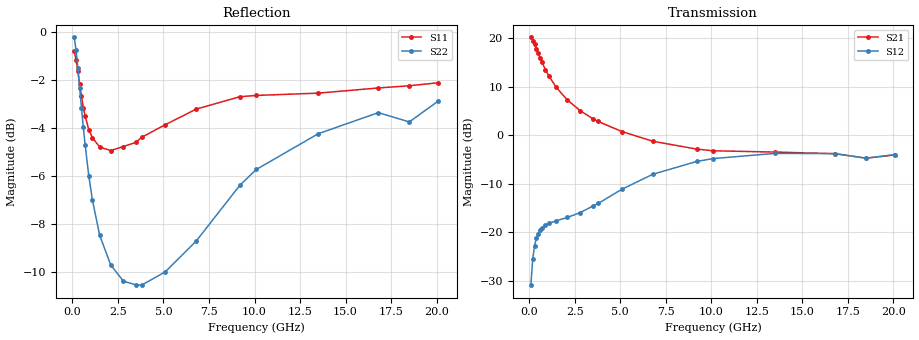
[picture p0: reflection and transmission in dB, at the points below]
!  Infineon Technologies AG
! BFR380L3 , PF131585-7, No.6, Th 09.10.01, soldered on pcb-board, measured with PP GSG850
!  Vce=4.0 V,  Ic=3.0 mA
! Common Emitter S-Parameters:  15. November 2001
#  GHz  S  MA  R  50
! f  S11  S21  S12  S22
! GHz  Mag  Ang  Mag  Ang  Mag  Ang  Mag  Ang
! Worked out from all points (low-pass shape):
!   201 points, 100 MHz to 20.1 GHz, reference 50 ohm
!   highest |S21| = 20.22 dB at 100 MHz (marker M1); lowest = -4.7 dB at 18.5 GHz (marker M2)
!   |S21| within 3 dB of the highest: start of sweep to 471.9 MHz
!   lowest |S11| = -4.9 dB at 2.1 GHz (marker M3), VSWR 3.62, Z = 13.8 - j1.7 ohm
!   |S11| at or under -10 dB: nowhere
!   |S22| runs from -10.5 to -0.2 dB; largest |S21 - S12| = 10
!   S11 on the Smith chart (normalised r, x): 100 MHz: 1.31, -5.09; 400 MHz: 0.35, -1.31; 1.1 GHz: 0.29, -0.38; 3.8 GHz: 0.27, +0.27; 9.2 GHz: 0.33, +1.06; 20.1 GHz: 1.00, +2.52
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0.1  0.9122 -20.9  10.25 165.9  0.02842 77.4  0.9749 -11.3
0.2  0.8767 -39.8  9.501 153.1  0.05261 68.3  0.9188 -21.5
0.3  0.83 -57.5  8.71 141.8  0.07195 59.9  0.8436 -30.0
0.4  0.7782 -72.4  7.847 132.2  0.08618 53.2  0.7653 -36.8
0.5  0.7345 -85.6  7.041 124.2  0.09653 48.2  0.6952 -42.2
0.6  0.6963 -97.0  6.334 117.5  0.1045 44.2  0.6342 -46.3
0.7  0.669 -106.9  5.73 111.7  0.1105 41.1  0.5823 -49.6
0.9  0.6269 -123.2  4.76 102.3  0.1183 37.4  0.5027 -54.5
1.1  0.6029 -136.0  4.057 94.8  0.1239 35.4  0.4473 -58.1
1.5  0.5765 -155.3  3.116 82.9  0.1311 34.7  0.3776 -63.5
2.1  0.5669 -175.8  2.316 69.1  0.1419 37.2  0.328 -71.1
2.8  0.5779 166.9  1.801 56.1  0.1591 42.3  0.3032 -81.6
3.5  0.5898 152.5  1.484 44.9  0.1857 46.9  0.2978 -93.0
3.8  0.6039 147.6  1.389 40.9  0.1982 48.2  0.2975 -99.3
5.1  0.6416 127.3  1.093 24.9  0.2776 49.0  0.317 -125.0
6.8  0.6914 105.8  0.868 10.3  0.3964 41.3  0.3675 -161.1
9.2  0.7338 83.7  0.7208 -1.7  0.5368 23.5  0.4802 157.3
10.1  0.7382 76.9  0.6923 -5.0  0.5749 16.6  0.5178 144.1
13.5  0.7464 58.7  0.6714 -18.7  0.6507 -7.6  0.6145 105.9
16.8  0.7651 47.2  0.6463 -30.5  0.6472 -24.8  0.6798 80.5
18.5  0.7732 45.6  0.5808 -38.2  0.5802 -33.5  0.6502 74.0
20.1  0.7846 38.4  0.6271 -42.1  0.6329 -38.9  0.7191 62.7
